# Generated deterministically by seda-macro-lef-normalizer-v1; recipe orfs-ng45-fakeram-metal3-coupledl2-pg-v1.
VERSION 5.8 ;
BUSBITCHARS "[]" ;
DIVIDERCHAR "/" ;

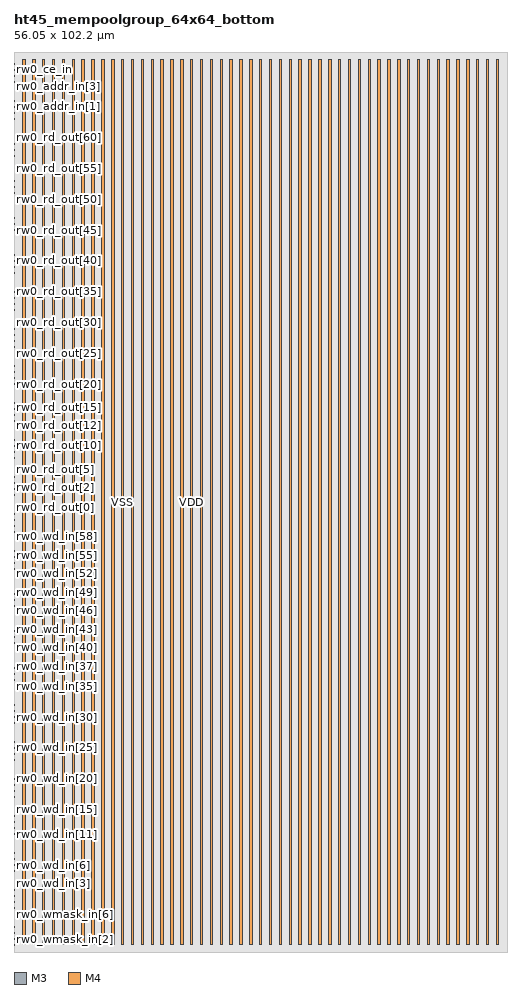
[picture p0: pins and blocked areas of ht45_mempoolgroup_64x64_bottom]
MACRO ht45_mempoolgroup_64x64_bottom
  FOREIGN ht45_mempoolgroup_64x64_bottom 0 0 ;
  CLASS COVER ;
  ORIGIN 0 0 ;
  SIZE 56.05 BY 102.2 ;
  SYMMETRY X Y R90 ;
  PIN rw0_wmask_in[0]
    DIRECTION INPUT ;
    USE SIGNAL ;
    SHAPE ABUTMENT ;
    PORT
      LAYER M3 ;
      RECT 0 0.035 0.07 0.105 ;
    END
  END rw0_wmask_in[0]
  PIN rw0_wmask_in[1]
    DIRECTION INPUT ;
    USE SIGNAL ;
    SHAPE ABUTMENT ;
    PORT
      LAYER M3 ;
      RECT 0 0.735 0.07 0.805 ;
    END
  END rw0_wmask_in[1]
  PIN rw0_wmask_in[2]
    DIRECTION INPUT ;
    USE SIGNAL ;
    SHAPE ABUTMENT ;
    PORT
      LAYER M3 ;
      RECT 0 1.435 0.07 1.505 ;
    END
  END rw0_wmask_in[2]
  PIN rw0_wmask_in[3]
    DIRECTION INPUT ;
    USE SIGNAL ;
    SHAPE ABUTMENT ;
    PORT
      LAYER M3 ;
      RECT 0 2.135 0.07 2.205 ;
    END
  END rw0_wmask_in[3]
  PIN rw0_wmask_in[4]
    DIRECTION INPUT ;
    USE SIGNAL ;
    SHAPE ABUTMENT ;
    PORT
      LAYER M3 ;
      RECT 0 2.835 0.07 2.905 ;
    END
  END rw0_wmask_in[4]
  PIN rw0_wmask_in[5]
    DIRECTION INPUT ;
    USE SIGNAL ;
    SHAPE ABUTMENT ;
    PORT
      LAYER M3 ;
      RECT 0 3.535 0.07 3.605 ;
    END
  END rw0_wmask_in[5]
  PIN rw0_wmask_in[6]
    DIRECTION INPUT ;
    USE SIGNAL ;
    SHAPE ABUTMENT ;
    PORT
      LAYER M3 ;
      RECT 0 4.235 0.07 4.305 ;
    END
  END rw0_wmask_in[6]
  PIN rw0_wmask_in[7]
    DIRECTION INPUT ;
    USE SIGNAL ;
    SHAPE ABUTMENT ;
    PORT
      LAYER M3 ;
      RECT 0 4.935 0.07 5.005 ;
    END
  END rw0_wmask_in[7]
  PIN rw0_wd_in[0]
    DIRECTION INPUT ;
    USE SIGNAL ;
    SHAPE ABUTMENT ;
    PORT
      LAYER M3 ;
      RECT 0 5.635 0.07 5.705 ;
    END
  END rw0_wd_in[0]
  PIN rw0_wd_in[1]
    DIRECTION INPUT ;
    USE SIGNAL ;
    SHAPE ABUTMENT ;
    PORT
      LAYER M3 ;
      RECT 0 6.335 0.07 6.405 ;
    END
  END rw0_wd_in[1]
  PIN rw0_wd_in[2]
    DIRECTION INPUT ;
    USE SIGNAL ;
    SHAPE ABUTMENT ;
    PORT
      LAYER M3 ;
      RECT 0 7.035 0.07 7.105 ;
    END
  END rw0_wd_in[2]
  PIN rw0_wd_in[3]
    DIRECTION INPUT ;
    USE SIGNAL ;
    SHAPE ABUTMENT ;
    PORT
      LAYER M3 ;
      RECT 0 7.735 0.07 7.805 ;
    END
  END rw0_wd_in[3]
  PIN rw0_wd_in[4]
    DIRECTION INPUT ;
    USE SIGNAL ;
    SHAPE ABUTMENT ;
    PORT
      LAYER M3 ;
      RECT 0 8.435 0.07 8.505 ;
    END
  END rw0_wd_in[4]
  PIN rw0_wd_in[5]
    DIRECTION INPUT ;
    USE SIGNAL ;
    SHAPE ABUTMENT ;
    PORT
      LAYER M3 ;
      RECT 0 9.135 0.07 9.205 ;
    END
  END rw0_wd_in[5]
  PIN rw0_wd_in[6]
    DIRECTION INPUT ;
    USE SIGNAL ;
    SHAPE ABUTMENT ;
    PORT
      LAYER M3 ;
      RECT 0 9.835 0.07 9.905 ;
    END
  END rw0_wd_in[6]
  PIN rw0_wd_in[7]
    DIRECTION INPUT ;
    USE SIGNAL ;
    SHAPE ABUTMENT ;
    PORT
      LAYER M3 ;
      RECT 0 10.535 0.07 10.605 ;
    END
  END rw0_wd_in[7]
  PIN rw0_wd_in[8]
    DIRECTION INPUT ;
    USE SIGNAL ;
    SHAPE ABUTMENT ;
    PORT
      LAYER M3 ;
      RECT 0 11.235 0.07 11.305 ;
    END
  END rw0_wd_in[8]
  PIN rw0_wd_in[9]
    DIRECTION INPUT ;
    USE SIGNAL ;
    SHAPE ABUTMENT ;
    PORT
      LAYER M3 ;
      RECT 0 11.935 0.07 12.005 ;
    END
  END rw0_wd_in[9]
  PIN rw0_wd_in[10]
    DIRECTION INPUT ;
    USE SIGNAL ;
    SHAPE ABUTMENT ;
    PORT
      LAYER M3 ;
      RECT 0 12.635 0.07 12.705 ;
    END
  END rw0_wd_in[10]
  PIN rw0_wd_in[11]
    DIRECTION INPUT ;
    USE SIGNAL ;
    SHAPE ABUTMENT ;
    PORT
      LAYER M3 ;
      RECT 0 13.335 0.07 13.405 ;
    END
  END rw0_wd_in[11]
  PIN rw0_wd_in[12]
    DIRECTION INPUT ;
    USE SIGNAL ;
    SHAPE ABUTMENT ;
    PORT
      LAYER M3 ;
      RECT 0 14.035 0.07 14.105 ;
    END
  END rw0_wd_in[12]
  PIN rw0_wd_in[13]
    DIRECTION INPUT ;
    USE SIGNAL ;
    SHAPE ABUTMENT ;
    PORT
      LAYER M3 ;
      RECT 0 14.735 0.07 14.805 ;
    END
  END rw0_wd_in[13]
  PIN rw0_wd_in[14]
    DIRECTION INPUT ;
    USE SIGNAL ;
    SHAPE ABUTMENT ;
    PORT
      LAYER M3 ;
      RECT 0 15.435 0.07 15.505 ;
    END
  END rw0_wd_in[14]
  PIN rw0_wd_in[15]
    DIRECTION INPUT ;
    USE SIGNAL ;
    SHAPE ABUTMENT ;
    PORT
      LAYER M3 ;
      RECT 0 16.135 0.07 16.205 ;
    END
  END rw0_wd_in[15]
  PIN rw0_wd_in[16]
    DIRECTION INPUT ;
    USE SIGNAL ;
    SHAPE ABUTMENT ;
    PORT
      LAYER M3 ;
      RECT 0 16.835 0.07 16.905 ;
    END
  END rw0_wd_in[16]
  PIN rw0_wd_in[17]
    DIRECTION INPUT ;
    USE SIGNAL ;
    SHAPE ABUTMENT ;
    PORT
      LAYER M3 ;
      RECT 0 17.535 0.07 17.605 ;
    END
  END rw0_wd_in[17]
  PIN rw0_wd_in[18]
    DIRECTION INPUT ;
    USE SIGNAL ;
    SHAPE ABUTMENT ;
    PORT
      LAYER M3 ;
      RECT 0 18.235 0.07 18.305 ;
    END
  END rw0_wd_in[18]
  PIN rw0_wd_in[19]
    DIRECTION INPUT ;
    USE SIGNAL ;
    SHAPE ABUTMENT ;
    PORT
      LAYER M3 ;
      RECT 0 18.935 0.07 19.005 ;
    END
  END rw0_wd_in[19]
  PIN rw0_wd_in[20]
    DIRECTION INPUT ;
    USE SIGNAL ;
    SHAPE ABUTMENT ;
    PORT
      LAYER M3 ;
      RECT 0 19.635 0.07 19.705 ;
    END
  END rw0_wd_in[20]
  PIN rw0_wd_in[21]
    DIRECTION INPUT ;
    USE SIGNAL ;
    SHAPE ABUTMENT ;
    PORT
      LAYER M3 ;
      RECT 0 20.335 0.07 20.405 ;
    END
  END rw0_wd_in[21]
  PIN rw0_wd_in[22]
    DIRECTION INPUT ;
    USE SIGNAL ;
    SHAPE ABUTMENT ;
    PORT
      LAYER M3 ;
      RECT 0 21.035 0.07 21.105 ;
    END
  END rw0_wd_in[22]
  PIN rw0_wd_in[23]
    DIRECTION INPUT ;
    USE SIGNAL ;
    SHAPE ABUTMENT ;
    PORT
      LAYER M3 ;
      RECT 0 21.735 0.07 21.805 ;
    END
  END rw0_wd_in[23]
  PIN rw0_wd_in[24]
    DIRECTION INPUT ;
    USE SIGNAL ;
    SHAPE ABUTMENT ;
    PORT
      LAYER M3 ;
      RECT 0 22.435 0.07 22.505 ;
    END
  END rw0_wd_in[24]
  PIN rw0_wd_in[25]
    DIRECTION INPUT ;
    USE SIGNAL ;
    SHAPE ABUTMENT ;
    PORT
      LAYER M3 ;
      RECT 0 23.135 0.07 23.205 ;
    END
  END rw0_wd_in[25]
  PIN rw0_wd_in[26]
    DIRECTION INPUT ;
    USE SIGNAL ;
    SHAPE ABUTMENT ;
    PORT
      LAYER M3 ;
      RECT 0 23.835 0.07 23.905 ;
    END
  END rw0_wd_in[26]
  PIN rw0_wd_in[27]
    DIRECTION INPUT ;
    USE SIGNAL ;
    SHAPE ABUTMENT ;
    PORT
      LAYER M3 ;
      RECT 0 24.535 0.07 24.605 ;
    END
  END rw0_wd_in[27]
  PIN rw0_wd_in[28]
    DIRECTION INPUT ;
    USE SIGNAL ;
    SHAPE ABUTMENT ;
    PORT
      LAYER M3 ;
      RECT 0 25.235 0.07 25.305 ;
    END
  END rw0_wd_in[28]
  PIN rw0_wd_in[29]
    DIRECTION INPUT ;
    USE SIGNAL ;
    SHAPE ABUTMENT ;
    PORT
      LAYER M3 ;
      RECT 0 25.935 0.07 26.005 ;
    END
  END rw0_wd_in[29]
  PIN rw0_wd_in[30]
    DIRECTION INPUT ;
    USE SIGNAL ;
    SHAPE ABUTMENT ;
    PORT
      LAYER M3 ;
      RECT 0 26.635 0.07 26.705 ;
    END
  END rw0_wd_in[30]
  PIN rw0_wd_in[31]
    DIRECTION INPUT ;
    USE SIGNAL ;
    SHAPE ABUTMENT ;
    PORT
      LAYER M3 ;
      RECT 0 27.335 0.07 27.405 ;
    END
  END rw0_wd_in[31]
  PIN rw0_wd_in[32]
    DIRECTION INPUT ;
    USE SIGNAL ;
    SHAPE ABUTMENT ;
    PORT
      LAYER M3 ;
      RECT 0 28.035 0.07 28.105 ;
    END
  END rw0_wd_in[32]
  PIN rw0_wd_in[33]
    DIRECTION INPUT ;
    USE SIGNAL ;
    SHAPE ABUTMENT ;
    PORT
      LAYER M3 ;
      RECT 0 28.735 0.07 28.805 ;
    END
  END rw0_wd_in[33]
  PIN rw0_wd_in[34]
    DIRECTION INPUT ;
    USE SIGNAL ;
    SHAPE ABUTMENT ;
    PORT
      LAYER M3 ;
      RECT 0 29.435 0.07 29.505 ;
    END
  END rw0_wd_in[34]
  PIN rw0_wd_in[35]
    DIRECTION INPUT ;
    USE SIGNAL ;
    SHAPE ABUTMENT ;
    PORT
      LAYER M3 ;
      RECT 0 30.135 0.07 30.205 ;
    END
  END rw0_wd_in[35]
  PIN rw0_wd_in[36]
    DIRECTION INPUT ;
    USE SIGNAL ;
    SHAPE ABUTMENT ;
    PORT
      LAYER M3 ;
      RECT 0 30.835 0.07 30.905 ;
    END
  END rw0_wd_in[36]
  PIN rw0_wd_in[37]
    DIRECTION INPUT ;
    USE SIGNAL ;
    SHAPE ABUTMENT ;
    PORT
      LAYER M3 ;
      RECT 0 31.535 0.07 31.605 ;
    END
  END rw0_wd_in[37]
  PIN rw0_wd_in[38]
    DIRECTION INPUT ;
    USE SIGNAL ;
    SHAPE ABUTMENT ;
    PORT
      LAYER M3 ;
      RECT 0 32.235 0.07 32.305 ;
    END
  END rw0_wd_in[38]
  PIN rw0_wd_in[39]
    DIRECTION INPUT ;
    USE SIGNAL ;
    SHAPE ABUTMENT ;
    PORT
      LAYER M3 ;
      RECT 0 32.935 0.07 33.005 ;
    END
  END rw0_wd_in[39]
  PIN rw0_wd_in[40]
    DIRECTION INPUT ;
    USE SIGNAL ;
    SHAPE ABUTMENT ;
    PORT
      LAYER M3 ;
      RECT 0 33.635 0.07 33.705 ;
    END
  END rw0_wd_in[40]
  PIN rw0_wd_in[41]
    DIRECTION INPUT ;
    USE SIGNAL ;
    SHAPE ABUTMENT ;
    PORT
      LAYER M3 ;
      RECT 0 34.335 0.07 34.405 ;
    END
  END rw0_wd_in[41]
  PIN rw0_wd_in[42]
    DIRECTION INPUT ;
    USE SIGNAL ;
    SHAPE ABUTMENT ;
    PORT
      LAYER M3 ;
      RECT 0 35.035 0.07 35.105 ;
    END
  END rw0_wd_in[42]
  PIN rw0_wd_in[43]
    DIRECTION INPUT ;
    USE SIGNAL ;
    SHAPE ABUTMENT ;
    PORT
      LAYER M3 ;
      RECT 0 35.735 0.07 35.805 ;
    END
  END rw0_wd_in[43]
  PIN rw0_wd_in[44]
    DIRECTION INPUT ;
    USE SIGNAL ;
    SHAPE ABUTMENT ;
    PORT
      LAYER M3 ;
      RECT 0 36.435 0.07 36.505 ;
    END
  END rw0_wd_in[44]
  PIN rw0_wd_in[45]
    DIRECTION INPUT ;
    USE SIGNAL ;
    SHAPE ABUTMENT ;
    PORT
      LAYER M3 ;
      RECT 0 37.135 0.07 37.205 ;
    END
  END rw0_wd_in[45]
  PIN rw0_wd_in[46]
    DIRECTION INPUT ;
    USE SIGNAL ;
    SHAPE ABUTMENT ;
    PORT
      LAYER M3 ;
      RECT 0 37.835 0.07 37.905 ;
    END
  END rw0_wd_in[46]
  PIN rw0_wd_in[47]
    DIRECTION INPUT ;
    USE SIGNAL ;
    SHAPE ABUTMENT ;
    PORT
      LAYER M3 ;
      RECT 0 38.535 0.07 38.605 ;
    END
  END rw0_wd_in[47]
  PIN rw0_wd_in[48]
    DIRECTION INPUT ;
    USE SIGNAL ;
    SHAPE ABUTMENT ;
    PORT
      LAYER M3 ;
      RECT 0 39.235 0.07 39.305 ;
    END
  END rw0_wd_in[48]
  PIN rw0_wd_in[49]
    DIRECTION INPUT ;
    USE SIGNAL ;
    SHAPE ABUTMENT ;
    PORT
      LAYER M3 ;
      RECT 0 39.935 0.07 40.005 ;
    END
  END rw0_wd_in[49]
  PIN rw0_wd_in[50]
    DIRECTION INPUT ;
    USE SIGNAL ;
    SHAPE ABUTMENT ;
    PORT
      LAYER M3 ;
      RECT 0 40.635 0.07 40.705 ;
    END
  END rw0_wd_in[50]
  PIN rw0_wd_in[51]
    DIRECTION INPUT ;
    USE SIGNAL ;
    SHAPE ABUTMENT ;
    PORT
      LAYER M3 ;
      RECT 0 41.335 0.07 41.405 ;
    END
  END rw0_wd_in[51]
  PIN rw0_wd_in[52]
    DIRECTION INPUT ;
    USE SIGNAL ;
    SHAPE ABUTMENT ;
    PORT
      LAYER M3 ;
      RECT 0 42.035 0.07 42.105 ;
    END
  END rw0_wd_in[52]
  PIN rw0_wd_in[53]
    DIRECTION INPUT ;
    USE SIGNAL ;
    SHAPE ABUTMENT ;
    PORT
      LAYER M3 ;
      RECT 0 42.735 0.07 42.805 ;
    END
  END rw0_wd_in[53]
  PIN rw0_wd_in[54]
    DIRECTION INPUT ;
    USE SIGNAL ;
    SHAPE ABUTMENT ;
    PORT
      LAYER M3 ;
      RECT 0 43.435 0.07 43.505 ;
    END
  END rw0_wd_in[54]
  PIN rw0_wd_in[55]
    DIRECTION INPUT ;
    USE SIGNAL ;
    SHAPE ABUTMENT ;
    PORT
      LAYER M3 ;
      RECT 0 44.135 0.07 44.205 ;
    END
  END rw0_wd_in[55]
  PIN rw0_wd_in[56]
    DIRECTION INPUT ;
    USE SIGNAL ;
    SHAPE ABUTMENT ;
    PORT
      LAYER M3 ;
      RECT 0 44.835 0.07 44.905 ;
    END
  END rw0_wd_in[56]
  PIN rw0_wd_in[57]
    DIRECTION INPUT ;
    USE SIGNAL ;
    SHAPE ABUTMENT ;
    PORT
      LAYER M3 ;
      RECT 0 45.535 0.07 45.605 ;
    END
  END rw0_wd_in[57]
  PIN rw0_wd_in[58]
    DIRECTION INPUT ;
    USE SIGNAL ;
    SHAPE ABUTMENT ;
    PORT
      LAYER M3 ;
      RECT 0 46.235 0.07 46.305 ;
    END
  END rw0_wd_in[58]
  PIN rw0_wd_in[59]
    DIRECTION INPUT ;
    USE SIGNAL ;
    SHAPE ABUTMENT ;
    PORT
      LAYER M3 ;
      RECT 0 46.935 0.07 47.005 ;
    END
  END rw0_wd_in[59]
  PIN rw0_wd_in[60]
    DIRECTION INPUT ;
    USE SIGNAL ;
    SHAPE ABUTMENT ;
    PORT
      LAYER M3 ;
      RECT 0 47.635 0.07 47.705 ;
    END
  END rw0_wd_in[60]
  PIN rw0_wd_in[61]
    DIRECTION INPUT ;
    USE SIGNAL ;
    SHAPE ABUTMENT ;
    PORT
      LAYER M3 ;
      RECT 0 48.335 0.07 48.405 ;
    END
  END rw0_wd_in[61]
  PIN rw0_wd_in[62]
    DIRECTION INPUT ;
    USE SIGNAL ;
    SHAPE ABUTMENT ;
    PORT
      LAYER M3 ;
      RECT 0 49.035 0.07 49.105 ;
    END
  END rw0_wd_in[62]
  PIN rw0_wd_in[63]
    DIRECTION INPUT ;
    USE SIGNAL ;
    SHAPE ABUTMENT ;
    PORT
      LAYER M3 ;
      RECT 0 49.735 0.07 49.805 ;
    END
  END rw0_wd_in[63]
  PIN rw0_rd_out[0]
    DIRECTION OUTPUT ;
    USE SIGNAL ;
    SHAPE ABUTMENT ;
    PORT
      LAYER M3 ;
      RECT 0 50.435 0.07 50.505 ;
    END
  END rw0_rd_out[0]
  PIN rw0_rd_out[1]
    DIRECTION OUTPUT ;
    USE SIGNAL ;
    SHAPE ABUTMENT ;
    PORT
      LAYER M3 ;
      RECT 0 51.135 0.07 51.205 ;
    END
  END rw0_rd_out[1]
  PIN rw0_rd_out[2]
    DIRECTION OUTPUT ;
    USE SIGNAL ;
    SHAPE ABUTMENT ;
    PORT
      LAYER M3 ;
      RECT 0 51.835 0.07 51.905 ;
    END
  END rw0_rd_out[2]
  PIN rw0_rd_out[3]
    DIRECTION OUTPUT ;
    USE SIGNAL ;
    SHAPE ABUTMENT ;
    PORT
      LAYER M3 ;
      RECT 0 52.535 0.07 52.605 ;
    END
  END rw0_rd_out[3]
  PIN rw0_rd_out[4]
    DIRECTION OUTPUT ;
    USE SIGNAL ;
    SHAPE ABUTMENT ;
    PORT
      LAYER M3 ;
      RECT 0 53.235 0.07 53.305 ;
    END
  END rw0_rd_out[4]
  PIN rw0_rd_out[5]
    DIRECTION OUTPUT ;
    USE SIGNAL ;
    SHAPE ABUTMENT ;
    PORT
      LAYER M3 ;
      RECT 0 53.935 0.07 54.005 ;
    END
  END rw0_rd_out[5]
  PIN rw0_rd_out[6]
    DIRECTION OUTPUT ;
    USE SIGNAL ;
    SHAPE ABUTMENT ;
    PORT
      LAYER M3 ;
      RECT 0 54.635 0.07 54.705 ;
    END
  END rw0_rd_out[6]
  PIN rw0_rd_out[7]
    DIRECTION OUTPUT ;
    USE SIGNAL ;
    SHAPE ABUTMENT ;
    PORT
      LAYER M3 ;
      RECT 0 55.335 0.07 55.405 ;
    END
  END rw0_rd_out[7]
  PIN rw0_rd_out[8]
    DIRECTION OUTPUT ;
    USE SIGNAL ;
    SHAPE ABUTMENT ;
    PORT
      LAYER M3 ;
      RECT 0 56.035 0.07 56.105 ;
    END
  END rw0_rd_out[8]
  PIN rw0_rd_out[9]
    DIRECTION OUTPUT ;
    USE SIGNAL ;
    SHAPE ABUTMENT ;
    PORT
      LAYER M3 ;
      RECT 0 56.735 0.07 56.805 ;
    END
  END rw0_rd_out[9]
  PIN rw0_rd_out[10]
    DIRECTION OUTPUT ;
    USE SIGNAL ;
    SHAPE ABUTMENT ;
    PORT
      LAYER M3 ;
      RECT 0 57.435 0.07 57.505 ;
    END
  END rw0_rd_out[10]
  PIN rw0_rd_out[11]
    DIRECTION OUTPUT ;
    USE SIGNAL ;
    SHAPE ABUTMENT ;
    PORT
      LAYER M3 ;
      RECT 0 58.135 0.07 58.205 ;
    END
  END rw0_rd_out[11]
  PIN rw0_rd_out[12]
    DIRECTION OUTPUT ;
    USE SIGNAL ;
    SHAPE ABUTMENT ;
    PORT
      LAYER M3 ;
      RECT 0 58.835 0.07 58.905 ;
    END
  END rw0_rd_out[12]
  PIN rw0_rd_out[13]
    DIRECTION OUTPUT ;
    USE SIGNAL ;
    SHAPE ABUTMENT ;
    PORT
      LAYER M3 ;
      RECT 0 59.535 0.07 59.605 ;
    END
  END rw0_rd_out[13]
  PIN rw0_rd_out[14]
    DIRECTION OUTPUT ;
    USE SIGNAL ;
    SHAPE ABUTMENT ;
    PORT
      LAYER M3 ;
      RECT 0 60.235 0.07 60.305 ;
    END
  END rw0_rd_out[14]
  PIN rw0_rd_out[15]
    DIRECTION OUTPUT ;
    USE SIGNAL ;
    SHAPE ABUTMENT ;
    PORT
      LAYER M3 ;
      RECT 0 60.935 0.07 61.005 ;
    END
  END rw0_rd_out[15]
  PIN rw0_rd_out[16]
    DIRECTION OUTPUT ;
    USE SIGNAL ;
    SHAPE ABUTMENT ;
    PORT
      LAYER M3 ;
      RECT 0 61.635 0.07 61.705 ;
    END
  END rw0_rd_out[16]
  PIN rw0_rd_out[17]
    DIRECTION OUTPUT ;
    USE SIGNAL ;
    SHAPE ABUTMENT ;
    PORT
      LAYER M3 ;
      RECT 0 62.335 0.07 62.405 ;
    END
  END rw0_rd_out[17]
  PIN rw0_rd_out[18]
    DIRECTION OUTPUT ;
    USE SIGNAL ;
    SHAPE ABUTMENT ;
    PORT
      LAYER M3 ;
      RECT 0 63.035 0.07 63.105 ;
    END
  END rw0_rd_out[18]
  PIN rw0_rd_out[19]
    DIRECTION OUTPUT ;
    USE SIGNAL ;
    SHAPE ABUTMENT ;
    PORT
      LAYER M3 ;
      RECT 0 63.735 0.07 63.805 ;
    END
  END rw0_rd_out[19]
  PIN rw0_rd_out[20]
    DIRECTION OUTPUT ;
    USE SIGNAL ;
    SHAPE ABUTMENT ;
    PORT
      LAYER M3 ;
      RECT 0 64.435 0.07 64.505 ;
    END
  END rw0_rd_out[20]
  PIN rw0_rd_out[21]
    DIRECTION OUTPUT ;
    USE SIGNAL ;
    SHAPE ABUTMENT ;
    PORT
      LAYER M3 ;
      RECT 0 65.135 0.07 65.205 ;
    END
  END rw0_rd_out[21]
  PIN rw0_rd_out[22]
    DIRECTION OUTPUT ;
    USE SIGNAL ;
    SHAPE ABUTMENT ;
    PORT
      LAYER M3 ;
      RECT 0 65.835 0.07 65.905 ;
    END
  END rw0_rd_out[22]
  PIN rw0_rd_out[23]
    DIRECTION OUTPUT ;
    USE SIGNAL ;
    SHAPE ABUTMENT ;
    PORT
      LAYER M3 ;
      RECT 0 66.535 0.07 66.605 ;
    END
  END rw0_rd_out[23]
  PIN rw0_rd_out[24]
    DIRECTION OUTPUT ;
    USE SIGNAL ;
    SHAPE ABUTMENT ;
    PORT
      LAYER M3 ;
      RECT 0 67.235 0.07 67.305 ;
    END
  END rw0_rd_out[24]
  PIN rw0_rd_out[25]
    DIRECTION OUTPUT ;
    USE SIGNAL ;
    SHAPE ABUTMENT ;
    PORT
      LAYER M3 ;
      RECT 0 67.935 0.07 68.005 ;
    END
  END rw0_rd_out[25]
  PIN rw0_rd_out[26]
    DIRECTION OUTPUT ;
    USE SIGNAL ;
    SHAPE ABUTMENT ;
    PORT
      LAYER M3 ;
      RECT 0 68.635 0.07 68.705 ;
    END
  END rw0_rd_out[26]
  PIN rw0_rd_out[27]
    DIRECTION OUTPUT ;
    USE SIGNAL ;
    SHAPE ABUTMENT ;
    PORT
      LAYER M3 ;
      RECT 0 69.335 0.07 69.405 ;
    END
  END rw0_rd_out[27]
  PIN rw0_rd_out[28]
    DIRECTION OUTPUT ;
    USE SIGNAL ;
    SHAPE ABUTMENT ;
    PORT
      LAYER M3 ;
      RECT 0 70.035 0.07 70.105 ;
    END
  END rw0_rd_out[28]
  PIN rw0_rd_out[29]
    DIRECTION OUTPUT ;
    USE SIGNAL ;
    SHAPE ABUTMENT ;
    PORT
      LAYER M3 ;
      RECT 0 70.735 0.07 70.805 ;
    END
  END rw0_rd_out[29]
  PIN rw0_rd_out[30]
    DIRECTION OUTPUT ;
    USE SIGNAL ;
    SHAPE ABUTMENT ;
    PORT
      LAYER M3 ;
      RECT 0 71.435 0.07 71.505 ;
    END
  END rw0_rd_out[30]
  PIN rw0_rd_out[31]
    DIRECTION OUTPUT ;
    USE SIGNAL ;
    SHAPE ABUTMENT ;
    PORT
      LAYER M3 ;
      RECT 0 72.135 0.07 72.205 ;
    END
  END rw0_rd_out[31]
  PIN rw0_rd_out[32]
    DIRECTION OUTPUT ;
    USE SIGNAL ;
    SHAPE ABUTMENT ;
    PORT
      LAYER M3 ;
      RECT 0 72.835 0.07 72.905 ;
    END
  END rw0_rd_out[32]
  PIN rw0_rd_out[33]
    DIRECTION OUTPUT ;
    USE SIGNAL ;
    SHAPE ABUTMENT ;
    PORT
      LAYER M3 ;
      RECT 0 73.535 0.07 73.605 ;
    END
  END rw0_rd_out[33]
  PIN rw0_rd_out[34]
    DIRECTION OUTPUT ;
    USE SIGNAL ;
    SHAPE ABUTMENT ;
    PORT
      LAYER M3 ;
      RECT 0 74.235 0.07 74.305 ;
    END
  END rw0_rd_out[34]
  PIN rw0_rd_out[35]
    DIRECTION OUTPUT ;
    USE SIGNAL ;
    SHAPE ABUTMENT ;
    PORT
      LAYER M3 ;
      RECT 0 74.935 0.07 75.005 ;
    END
  END rw0_rd_out[35]
  PIN rw0_rd_out[36]
    DIRECTION OUTPUT ;
    USE SIGNAL ;
    SHAPE ABUTMENT ;
    PORT
      LAYER M3 ;
      RECT 0 75.635 0.07 75.705 ;
    END
  END rw0_rd_out[36]
  PIN rw0_rd_out[37]
    DIRECTION OUTPUT ;
    USE SIGNAL ;
    SHAPE ABUTMENT ;
    PORT
      LAYER M3 ;
      RECT 0 76.335 0.07 76.405 ;
    END
  END rw0_rd_out[37]
  PIN rw0_rd_out[38]
    DIRECTION OUTPUT ;
    USE SIGNAL ;
    SHAPE ABUTMENT ;
    PORT
      LAYER M3 ;
      RECT 0 77.035 0.07 77.105 ;
    END
  END rw0_rd_out[38]
  PIN rw0_rd_out[39]
    DIRECTION OUTPUT ;
    USE SIGNAL ;
    SHAPE ABUTMENT ;
    PORT
      LAYER M3 ;
      RECT 0 77.735 0.07 77.805 ;
    END
  END rw0_rd_out[39]
  PIN rw0_rd_out[40]
    DIRECTION OUTPUT ;
    USE SIGNAL ;
    SHAPE ABUTMENT ;
    PORT
      LAYER M3 ;
      RECT 0 78.435 0.07 78.505 ;
    END
  END rw0_rd_out[40]
  PIN rw0_rd_out[41]
    DIRECTION OUTPUT ;
    USE SIGNAL ;
    SHAPE ABUTMENT ;
    PORT
      LAYER M3 ;
      RECT 0 79.135 0.07 79.205 ;
    END
  END rw0_rd_out[41]
  PIN rw0_rd_out[42]
    DIRECTION OUTPUT ;
    USE SIGNAL ;
    SHAPE ABUTMENT ;
    PORT
      LAYER M3 ;
      RECT 0 79.835 0.07 79.905 ;
    END
  END rw0_rd_out[42]
  PIN rw0_rd_out[43]
    DIRECTION OUTPUT ;
    USE SIGNAL ;
    SHAPE ABUTMENT ;
    PORT
      LAYER M3 ;
      RECT 0 80.535 0.07 80.605 ;
    END
  END rw0_rd_out[43]
  PIN rw0_rd_out[44]
    DIRECTION OUTPUT ;
    USE SIGNAL ;
    SHAPE ABUTMENT ;
    PORT
      LAYER M3 ;
      RECT 0 81.235 0.07 81.305 ;
    END
  END rw0_rd_out[44]
  PIN rw0_rd_out[45]
    DIRECTION OUTPUT ;
    USE SIGNAL ;
    SHAPE ABUTMENT ;
    PORT
      LAYER M3 ;
      RECT 0 81.935 0.07 82.005 ;
    END
  END rw0_rd_out[45]
  PIN rw0_rd_out[46]
    DIRECTION OUTPUT ;
    USE SIGNAL ;
    SHAPE ABUTMENT ;
    PORT
      LAYER M3 ;
      RECT 0 82.635 0.07 82.705 ;
    END
  END rw0_rd_out[46]
  PIN rw0_rd_out[47]
    DIRECTION OUTPUT ;
    USE SIGNAL ;
    SHAPE ABUTMENT ;
    PORT
      LAYER M3 ;
      RECT 0 83.335 0.07 83.405 ;
    END
  END rw0_rd_out[47]
  PIN rw0_rd_out[48]
    DIRECTION OUTPUT ;
    USE SIGNAL ;
    SHAPE ABUTMENT ;
    PORT
      LAYER M3 ;
      RECT 0 84.035 0.07 84.105 ;
    END
  END rw0_rd_out[48]
  PIN rw0_rd_out[49]
    DIRECTION OUTPUT ;
    USE SIGNAL ;
    SHAPE ABUTMENT ;
    PORT
      LAYER M3 ;
      RECT 0 84.735 0.07 84.805 ;
    END
  END rw0_rd_out[49]
  PIN rw0_rd_out[50]
    DIRECTION OUTPUT ;
    USE SIGNAL ;
    SHAPE ABUTMENT ;
    PORT
      LAYER M3 ;
      RECT 0 85.435 0.07 85.505 ;
    END
  END rw0_rd_out[50]
  PIN rw0_rd_out[51]
    DIRECTION OUTPUT ;
    USE SIGNAL ;
    SHAPE ABUTMENT ;
    PORT
      LAYER M3 ;
      RECT 0 86.135 0.07 86.205 ;
    END
  END rw0_rd_out[51]
  PIN rw0_rd_out[52]
    DIRECTION OUTPUT ;
    USE SIGNAL ;
    SHAPE ABUTMENT ;
    PORT
      LAYER M3 ;
      RECT 0 86.835 0.07 86.905 ;
    END
  END rw0_rd_out[52]
  PIN rw0_rd_out[53]
    DIRECTION OUTPUT ;
    USE SIGNAL ;
    SHAPE ABUTMENT ;
    PORT
      LAYER M3 ;
      RECT 0 87.535 0.07 87.605 ;
    END
  END rw0_rd_out[53]
  PIN rw0_rd_out[54]
    DIRECTION OUTPUT ;
    USE SIGNAL ;
    SHAPE ABUTMENT ;
    PORT
      LAYER M3 ;
      RECT 0 88.235 0.07 88.305 ;
    END
  END rw0_rd_out[54]
  PIN rw0_rd_out[55]
    DIRECTION OUTPUT ;
    USE SIGNAL ;
    SHAPE ABUTMENT ;
    PORT
      LAYER M3 ;
      RECT 0 88.935 0.07 89.005 ;
    END
  END rw0_rd_out[55]
  PIN rw0_rd_out[56]
    DIRECTION OUTPUT ;
    USE SIGNAL ;
    SHAPE ABUTMENT ;
    PORT
      LAYER M3 ;
      RECT 0 89.635 0.07 89.705 ;
    END
  END rw0_rd_out[56]
  PIN rw0_rd_out[57]
    DIRECTION OUTPUT ;
    USE SIGNAL ;
    SHAPE ABUTMENT ;
    PORT
      LAYER M3 ;
      RECT 0 90.335 0.07 90.405 ;
    END
  END rw0_rd_out[57]
  PIN rw0_rd_out[58]
    DIRECTION OUTPUT ;
    USE SIGNAL ;
    SHAPE ABUTMENT ;
    PORT
      LAYER M3 ;
      RECT 0 91.035 0.07 91.105 ;
    END
  END rw0_rd_out[58]
  PIN rw0_rd_out[59]
    DIRECTION OUTPUT ;
    USE SIGNAL ;
    SHAPE ABUTMENT ;
    PORT
      LAYER M3 ;
      RECT 0 91.735 0.07 91.805 ;
    END
  END rw0_rd_out[59]
  PIN rw0_rd_out[60]
    DIRECTION OUTPUT ;
    USE SIGNAL ;
    SHAPE ABUTMENT ;
    PORT
      LAYER M3 ;
      RECT 0 92.435 0.07 92.505 ;
    END
  END rw0_rd_out[60]
  PIN rw0_rd_out[61]
    DIRECTION OUTPUT ;
    USE SIGNAL ;
    SHAPE ABUTMENT ;
    PORT
      LAYER M3 ;
      RECT 0 93.135 0.07 93.205 ;
    END
  END rw0_rd_out[61]
  PIN rw0_rd_out[62]
    DIRECTION OUTPUT ;
    USE SIGNAL ;
    SHAPE ABUTMENT ;
    PORT
      LAYER M3 ;
      RECT 0 93.835 0.07 93.905 ;
    END
  END rw0_rd_out[62]
  PIN rw0_rd_out[63]
    DIRECTION OUTPUT ;
    USE SIGNAL ;
    SHAPE ABUTMENT ;
    PORT
      LAYER M3 ;
      RECT 0 94.535 0.07 94.605 ;
    END
  END rw0_rd_out[63]
  PIN rw0_addr_in[0]
    DIRECTION INPUT ;
    USE SIGNAL ;
    SHAPE ABUTMENT ;
    PORT
      LAYER M3 ;
      RECT 0 95.235 0.07 95.305 ;
    END
  END rw0_addr_in[0]
  PIN rw0_addr_in[1]
    DIRECTION INPUT ;
    USE SIGNAL ;
    SHAPE ABUTMENT ;
    PORT
      LAYER M3 ;
      RECT 0 95.935 0.07 96.005 ;
    END
  END rw0_addr_in[1]
  PIN rw0_addr_in[2]
    DIRECTION INPUT ;
    USE SIGNAL ;
    SHAPE ABUTMENT ;
    PORT
      LAYER M3 ;
      RECT 0 96.635 0.07 96.705 ;
    END
  END rw0_addr_in[2]
  PIN rw0_addr_in[3]
    DIRECTION INPUT ;
    USE SIGNAL ;
    SHAPE ABUTMENT ;
    PORT
      LAYER M3 ;
      RECT 0 97.335 0.07 97.405 ;
    END
  END rw0_addr_in[3]
  PIN rw0_addr_in[4]
    DIRECTION INPUT ;
    USE SIGNAL ;
    SHAPE ABUTMENT ;
    PORT
      LAYER M3 ;
      RECT 0 98.035 0.07 98.105 ;
    END
  END rw0_addr_in[4]
  PIN rw0_addr_in[5]
    DIRECTION INPUT ;
    USE SIGNAL ;
    SHAPE ABUTMENT ;
    PORT
      LAYER M3 ;
      RECT 0 98.735 0.07 98.805 ;
    END
  END rw0_addr_in[5]
  PIN rw0_we_in
    DIRECTION INPUT ;
    USE SIGNAL ;
    SHAPE ABUTMENT ;
    PORT
      LAYER M3 ;
      RECT 0 99.435 0.07 99.505 ;
    END
  END rw0_we_in
  PIN rw0_ce_in
    DIRECTION INPUT ;
    USE SIGNAL ;
    SHAPE ABUTMENT ;
    PORT
      LAYER M3 ;
      RECT 0 100.135 0.07 100.205 ;
    END
  END rw0_ce_in
  PIN rw0_clk
    DIRECTION INPUT ;
    USE SIGNAL ;
    SHAPE ABUTMENT ;
    PORT
      LAYER M3 ;
      RECT 0 100.835 0.07 100.905 ;
    END
  END rw0_clk
  PIN VSS
    DIRECTION INOUT ;
    USE GROUND ;
    PORT
      LAYER M4 ;
      RECT 1 0.84 1.28 101.36 ;
      RECT 3.24 0.84 3.52 101.36 ;
      RECT 5.48 0.84 5.76 101.36 ;
      RECT 7.72 0.84 8 101.36 ;
      RECT 9.96 0.84 10.24 101.36 ;
      RECT 12.2 0.84 12.48 101.36 ;
      RECT 14.44 0.84 14.72 101.36 ;
      RECT 16.68 0.84 16.96 101.36 ;
      RECT 18.92 0.84 19.2 101.36 ;
      RECT 21.16 0.84 21.44 101.36 ;
      RECT 23.4 0.84 23.68 101.36 ;
      RECT 25.64 0.84 25.92 101.36 ;
      RECT 27.88 0.84 28.16 101.36 ;
      RECT 30.12 0.84 30.4 101.36 ;
      RECT 32.36 0.84 32.64 101.36 ;
      RECT 34.6 0.84 34.88 101.36 ;
      RECT 36.84 0.84 37.12 101.36 ;
      RECT 39.08 0.84 39.36 101.36 ;
      RECT 41.32 0.84 41.6 101.36 ;
      RECT 43.56 0.84 43.84 101.36 ;
      RECT 45.8 0.84 46.08 101.36 ;
      RECT 48.04 0.84 48.32 101.36 ;
      RECT 50.28 0.84 50.56 101.36 ;
      RECT 52.52 0.84 52.8 101.36 ;
      RECT 54.76 0.84 55.04 101.36 ;
    END
  END VSS
  PIN VDD
    DIRECTION INOUT ;
    USE POWER ;
    PORT
      LAYER M4 ;
      RECT 2.12 0.84 2.4 101.36 ;
      RECT 4.36 0.84 4.64 101.36 ;
      RECT 6.6 0.84 6.88 101.36 ;
      RECT 8.84 0.84 9.12 101.36 ;
      RECT 11.08 0.84 11.36 101.36 ;
      RECT 13.32 0.84 13.6 101.36 ;
      RECT 15.56 0.84 15.84 101.36 ;
      RECT 17.8 0.84 18.08 101.36 ;
      RECT 20.04 0.84 20.32 101.36 ;
      RECT 22.28 0.84 22.56 101.36 ;
      RECT 24.52 0.84 24.8 101.36 ;
      RECT 26.76 0.84 27.04 101.36 ;
      RECT 29 0.84 29.28 101.36 ;
      RECT 31.24 0.84 31.52 101.36 ;
      RECT 33.48 0.84 33.76 101.36 ;
      RECT 35.72 0.84 36 101.36 ;
      RECT 37.96 0.84 38.24 101.36 ;
      RECT 40.2 0.84 40.48 101.36 ;
      RECT 42.44 0.84 42.72 101.36 ;
      RECT 44.68 0.84 44.96 101.36 ;
      RECT 46.92 0.84 47.2 101.36 ;
      RECT 49.16 0.84 49.44 101.36 ;
      RECT 51.4 0.84 51.68 101.36 ;
      RECT 53.64 0.84 53.92 101.36 ;
    END
  END VDD
  OBS
    LAYER M1 ;
    RECT 0 0 56.05 102.2 ;
    LAYER M2 ;
    RECT 0 0 56.05 102.2 ;
  END
END ht45_mempoolgroup_64x64_bottom

END LIBRARY
